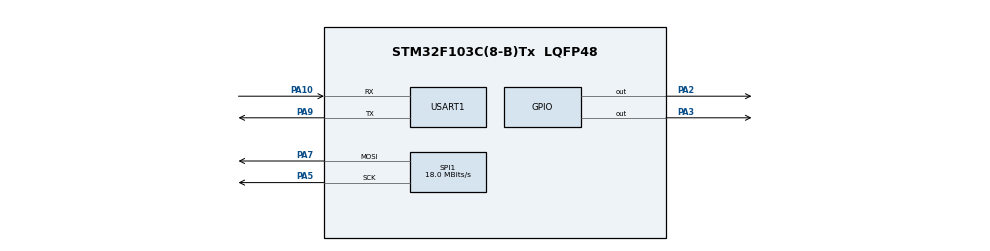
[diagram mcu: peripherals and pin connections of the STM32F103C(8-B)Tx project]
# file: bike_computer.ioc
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Dma.Request0=SPI1_TX
Dma.SPI1_TX.0.Direction=DMA_MEMORY_TO_PERIPH
Dma.SPI1_TX.0.Instance=DMA1_Channel3
Dma.SPI1_TX.0.MemDataAlignment=DMA_MDATAALIGN_BYTE
Dma.SPI1_TX.0.MemInc=DMA_MINC_ENABLE
Dma.SPI1_TX.0.Mode=DMA_NORMAL
Dma.SPI1_TX.0.PeriphDataAlignment=DMA_PDATAALIGN_BYTE
Dma.SPI1_TX.0.PeriphInc=DMA_PINC_DISABLE
Dma.SPI1_TX.0.Priority=DMA_PRIORITY_LOW
Mcu.Family=STM32F1
Mcu.Name=STM32F103C(8-B)Tx
Mcu.Package=LQFP48
NVIC.DMA1_Channel3_IRQn=true\:0\:0\:false\:false\:true\:false\:true
NVIC.PriorityGroup=NVIC_PRIORITYGROUP_4
PA10.Mode=Asynchronous
PA10.Signal=USART1_RX
PA13.Mode=Serial_Wire
PA13.Signal=SYS_JTMS-SWDIO
PA14.Mode=Serial_Wire
PA14.Signal=SYS_JTCK-SWCLK
PA2.Signal=GPIO_Output
PA3.Signal=GPIO_Output
PA5.Mode=TX_Only_Simplex_Unidirect_Master
PA5.Signal=SPI1_SCK
PA7.Mode=TX_Only_Simplex_Unidirect_Master
PA7.Signal=SPI1_MOSI
PA9.Mode=Asynchronous
PA9.Signal=USART1_TX
PC14-OSC32_IN.Mode=LSE-External-Oscillator
PC14-OSC32_IN.Signal=RCC_OSC32_IN
PC15-OSC32_OUT.Mode=LSE-External-Oscillator
PC15-OSC32_OUT.Signal=RCC_OSC32_OUT
PD0-OSC_IN.Mode=HSE-External-Oscillator
PD0-OSC_IN.Signal=RCC_OSC_IN
PD1-OSC_OUT.Mode=HSE-External-Oscillator
PD1-OSC_OUT.Signal=RCC_OSC_OUT
ProjectManager.HeapSize=0x200
ProjectManager.StackSize=0x400
ProjectManager.TargetToolchain=STM32CubeIDE
RCC.AHBFreq_Value=72000000
RCC.APB1CLKDivider=RCC_HCLK_DIV2
RCC.APB1Freq_Value=36000000
RCC.APB1TimFreq_Value=72000000
RCC.APB2Freq_Value=72000000
RCC.APB2TimFreq_Value=72000000
RCC.HCLKFreq_Value=72000000
RCC.PLLMUL=RCC_PLL_MUL9
RCC.PLLSourceVirtual=RCC_PLLSOURCE_HSE
RCC.SYSCLKFreq_VALUE=72000000
RCC.SYSCLKSource=RCC_SYSCLKSOURCE_PLLCLK
RCC.USBFreq_Value=72000000
SPI1.BaudRatePrescaler=SPI_BAUDRATEPRESCALER_4
SPI1.CLKPolarity=SPI_POLARITY_HIGH
SPI1.CalculateBaudRate=18.0 MBits/s
SPI1.Direction=SPI_DIRECTION_2LINES
SPI1.Mode=SPI_MODE_MASTER
SPI1.VirtualType=VM_MASTER
TIM2.Period=0xffff -1
TIM2.Prescaler=71
TIM3.Prescaler=36000
USART1.VirtualMode=VM_ASYNC
VP_TIM1_VS_ClockSourceINT.Mode=Internal
VP_TIM2_VS_ClockSourceINT.Mode=Internal
VP_TIM3_VS_ClockSourceINT.Mode=Internal
board=custom

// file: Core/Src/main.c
/* USER CODE BEGIN Header */
/**
  ******************************************************************************
  * @file           : main.c
  * @brief          : Main program body
  ******************************************************************************
  * @attention
  *
  * <h2><center>&copy; Copyright (c) 2020 STMicroelectronics.
  * All rights reserved.</center></h2>
  *
  * This software component is licensed by ST under BSD 3-Clause license,
  * the "License"; You may not use this file except in compliance with the
  * License. You may obtain a copy of the License at:
  *                        opensource.org/licenses/BSD-3-Clause
  *
  ******************************************************************************
  */
/* USER CODE END Header */

#include "main.h"

SPI_HandleTypeDef hspi1;
DMA_HandleTypeDef hdma_spi1_tx;

TIM_HandleTypeDef htim1;
TIM_HandleTypeDef htim2;
TIM_HandleTypeDef htim3;

UART_HandleTypeDef huart1;

void SystemClock_Config(void);
static void MX_GPIO_Init(void);
static void MX_DMA_Init(void);
static void MX_SPI1_Init(void);
static void MX_TIM1_Init(void);
static void MX_TIM2_Init(void);
static void MX_TIM3_Init(void);
static void MX_USART1_UART_Init(void);

int main(void)
{

  /* MCU Configuration--------------------------------------------------------*/

  /* Reset of all peripherals, Initializes the Flash interface and the Systick. */
  HAL_Init();

  /* Configure the system clock */
  SystemClock_Config();

  /* Initialize all configured peripherals */
  MX_GPIO_Init();
  MX_DMA_Init();
  MX_SPI1_Init();
  MX_TIM1_Init();
  MX_TIM2_Init();
  MX_TIM3_Init();
  MX_USART1_UART_Init();

  /* Infinite loop */
  while (1)
  {

  }
}

void SystemClock_Config(void)
{
  RCC_OscInitTypeDef RCC_OscInitStruct = {0};
  RCC_ClkInitTypeDef RCC_ClkInitStruct = {0};

  /** Initializes the CPU, AHB and APB busses clocks
  */
  RCC_OscInitStruct.OscillatorType = RCC_OSCILLATORTYPE_HSI;
  RCC_OscInitStruct.HSIState = RCC_HSI_ON;
  RCC_OscInitStruct.HSICalibrationValue = RCC_HSICALIBRATION_DEFAULT;
  RCC_OscInitStruct.PLL.PLLState = RCC_PLL_NONE;
  if (HAL_RCC_OscConfig(&RCC_OscInitStruct) != HAL_OK)
  {
    Error_Handler();
  }
  /** Initializes the CPU, AHB and APB busses clocks
  */
  RCC_ClkInitStruct.ClockType = RCC_CLOCKTYPE_HCLK|RCC_CLOCKTYPE_SYSCLK
                              |RCC_CLOCKTYPE_PCLK1|RCC_CLOCKTYPE_PCLK2;
  RCC_ClkInitStruct.SYSCLKSource = RCC_SYSCLKSOURCE_HSI;
  RCC_ClkInitStruct.AHBCLKDivider = RCC_SYSCLK_DIV1;
  RCC_ClkInitStruct.APB1CLKDivider = RCC_HCLK_DIV1;
  RCC_ClkInitStruct.APB2CLKDivider = RCC_HCLK_DIV1;

  if (HAL_RCC_ClockConfig(&RCC_ClkInitStruct, FLASH_LATENCY_0) != HAL_OK)
  {
    Error_Handler();
  }
}

static void MX_SPI1_Init(void)
{

  /* SPI1 parameter configuration*/
  hspi1.Instance = SPI1;
  hspi1.Init.Mode = SPI_MODE_MASTER;
  hspi1.Init.Direction = SPI_DIRECTION_2LINES;
  hspi1.Init.DataSize = SPI_DATASIZE_8BIT;
  hspi1.Init.CLKPolarity = SPI_POLARITY_HIGH;
  hspi1.Init.CLKPhase = SPI_PHASE_1EDGE;
  hspi1.Init.NSS = SPI_NSS_SOFT;
  hspi1.Init.BaudRatePrescaler = SPI_BAUDRATEPRESCALER_4;
  hspi1.Init.FirstBit = SPI_FIRSTBIT_MSB;
  hspi1.Init.TIMode = SPI_TIMODE_DISABLE;
  hspi1.Init.CRCCalculation = SPI_CRCCALCULATION_DISABLE;
  hspi1.Init.CRCPolynomial = 10;
  if (HAL_SPI_Init(&hspi1) != HAL_OK)
  {
    Error_Handler();
  }

}

static void MX_TIM1_Init(void)
{

  TIM_ClockConfigTypeDef sClockSourceConfig = {0};
  TIM_MasterConfigTypeDef sMasterConfig = {0};

  htim1.Instance = TIM1;
  htim1.Init.Prescaler = 0;
  htim1.Init.CounterMode = TIM_COUNTERMODE_UP;
  htim1.Init.Period = 0;
  htim1.Init.ClockDivision = TIM_CLOCKDIVISION_DIV1;
  htim1.Init.RepetitionCounter = 0;
  htim1.Init.AutoReloadPreload = TIM_AUTORELOAD_PRELOAD_DISABLE;
  if (HAL_TIM_Base_Init(&htim1) != HAL_OK)
  {
    Error_Handler();
  }
  sClockSourceConfig.ClockSource = TIM_CLOCKSOURCE_INTERNAL;
  if (HAL_TIM_ConfigClockSource(&htim1, &sClockSourceConfig) != HAL_OK)
  {
    Error_Handler();
  }
  sMasterConfig.MasterOutputTrigger = TIM_TRGO_RESET;
  sMasterConfig.MasterSlaveMode = TIM_MASTERSLAVEMODE_DISABLE;
  if (HAL_TIMEx_MasterConfigSynchronization(&htim1, &sMasterConfig) != HAL_OK)
  {
    Error_Handler();
  }

}

static void MX_TIM2_Init(void)
{

  TIM_ClockConfigTypeDef sClockSourceConfig = {0};
  TIM_MasterConfigTypeDef sMasterConfig = {0};

  htim2.Instance = TIM2;
  htim2.Init.Prescaler = 71;
  htim2.Init.CounterMode = TIM_COUNTERMODE_UP;
  htim2.Init.Period = 0xffff -1;
  htim2.Init.ClockDivision = TIM_CLOCKDIVISION_DIV1;
  htim2.Init.AutoReloadPreload = TIM_AUTORELOAD_PRELOAD_DISABLE;
  if (HAL_TIM_Base_Init(&htim2) != HAL_OK)
  {
    Error_Handler();
  }
  sClockSourceConfig.ClockSource = TIM_CLOCKSOURCE_INTERNAL;
  if (HAL_TIM_ConfigClockSource(&htim2, &sClockSourceConfig) != HAL_OK)
  {
    Error_Handler();
  }
  sMasterConfig.MasterOutputTrigger = TIM_TRGO_RESET;
  sMasterConfig.MasterSlaveMode = TIM_MASTERSLAVEMODE_DISABLE;
  if (HAL_TIMEx_MasterConfigSynchronization(&htim2, &sMasterConfig) != HAL_OK)
  {
    Error_Handler();
  }

}

static void MX_TIM3_Init(void)
{

  TIM_ClockConfigTypeDef sClockSourceConfig = {0};
  TIM_MasterConfigTypeDef sMasterConfig = {0};

  htim3.Instance = TIM3;
  htim3.Init.Prescaler = 36000;
  htim3.Init.CounterMode = TIM_COUNTERMODE_UP;
  htim3.Init.Period = 0;
  htim3.Init.ClockDivision = TIM_CLOCKDIVISION_DIV1;
  htim3.Init.AutoReloadPreload = TIM_AUTORELOAD_PRELOAD_DISABLE;
  if (HAL_TIM_Base_Init(&htim3) != HAL_OK)
  {
    Error_Handler();
  }
  sClockSourceConfig.ClockSource = TIM_CLOCKSOURCE_INTERNAL;
  if (HAL_TIM_ConfigClockSource(&htim3, &sClockSourceConfig) != HAL_OK)
  {
    Error_Handler();
  }
  sMasterConfig.MasterOutputTrigger = TIM_TRGO_RESET;
  sMasterConfig.MasterSlaveMode = TIM_MASTERSLAVEMODE_DISABLE;
  if (HAL_TIMEx_MasterConfigSynchronization(&htim3, &sMasterConfig) != HAL_OK)
  {
    Error_Handler();
  }

}

static void MX_USART1_UART_Init(void)
{

  huart1.Instance = USART1;
  huart1.Init.BaudRate = 115200;
  huart1.Init.WordLength = UART_WORDLENGTH_8B;
  huart1.Init.StopBits = UART_STOPBITS_1;
  huart1.Init.Parity = UART_PARITY_NONE;
  huart1.Init.Mode = UART_MODE_TX_RX;
  huart1.Init.HwFlowCtl = UART_HWCONTROL_NONE;
  huart1.Init.OverSampling = UART_OVERSAMPLING_16;
  if (HAL_UART_Init(&huart1) != HAL_OK)
  {
    Error_Handler();
  }

}

static void MX_DMA_Init(void)
{

  /* DMA controller clock enable */
  __HAL_RCC_DMA1_CLK_ENABLE();

  /* DMA interrupt init */
  /* DMA1_Channel3_IRQn interrupt configuration */
  HAL_NVIC_SetPriority(DMA1_Channel3_IRQn, 0, 0);
  HAL_NVIC_EnableIRQ(DMA1_Channel3_IRQn);

}

static void MX_GPIO_Init(void)
{

  /* GPIO Ports Clock Enable */
  __HAL_RCC_GPIOC_CLK_ENABLE();
  __HAL_RCC_GPIOD_CLK_ENABLE();
  __HAL_RCC_GPIOA_CLK_ENABLE();

}

void Error_Handler(void)
{
}

/************************ (C) COPYRIGHT STMicroelectronics *****END OF FILE****/
